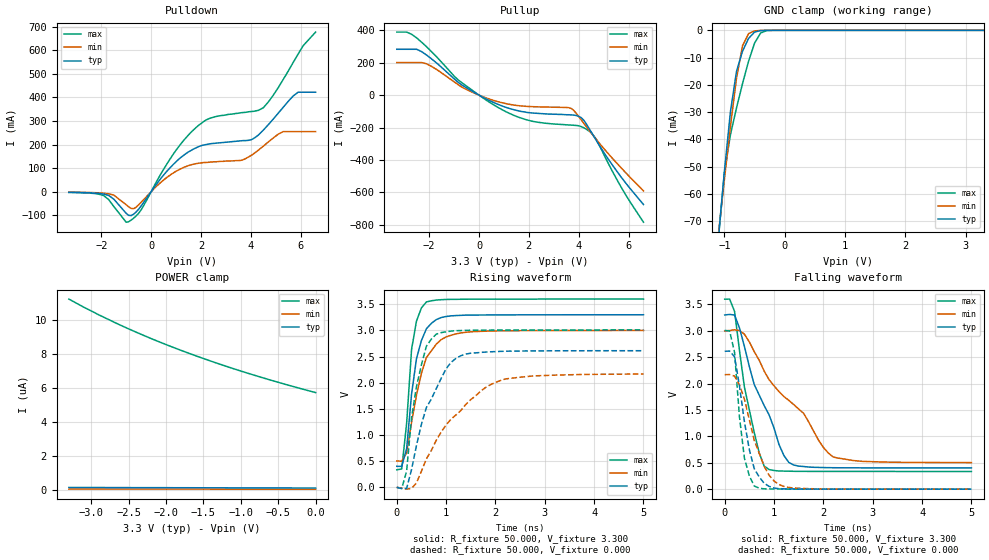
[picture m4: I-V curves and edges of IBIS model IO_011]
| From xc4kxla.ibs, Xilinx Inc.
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|   Model IO_011
[Model]   IO_011
Model_type   I/O
Polarity   Non-Inverting
Enable   Active-Low
Vinl =   0.800V
Vinh =   2.000V
Vmeas =   1.650V
Cref =  50.000pF
Rref =   1.000M
Vref =  0.000V
C_comp   7.300pF   5.500pF   8.800pF
[Temperature Range]   50.000   100.000   0.000
[Voltage Range]   3.300V   3.000V   3.600V
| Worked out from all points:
|   slope of the pulldown table from 0 to 0.495 V, typ, clamps not added: 7.07 ohm
|   slope of the pullup table from 0 to 0.495 V, typ, clamps not added: 12.6 ohm
|   GND clamp passes 1 mA (typ) near -0.52 V on its own axis
|   rising waveform, R_fixture 50.000, V_fixture 3.300: 20-80 % time 251ps typ, 356ps min, 184ps max; typ from 0.402 V to 3.3 V
|   rising waveform, R_fixture 50.000, V_fixture 0.000: 20-80 % time 564ps typ, 1.02ns min, 290ps max; typ from 0 V to 2.61 V
|   falling waveform, R_fixture 50.000, V_fixture 3.300: 20-80 % time 661ps typ, 1.19ns min, 364ps max; typ from 3.3 V to 0.403 V
|   falling waveform, R_fixture 50.000, V_fixture 0.000: 20-80 % time 287ps typ, 411ps min, 183ps max; typ from 2.61 V to 0.001 V
[Pulldown]
| voltage   I(typ)   I(min)   I(max)
-3.3V     -2.3mA     -1.8mA     -2.8mA
-1.9V     -9.7mA     -6.1mA     -16.3mA
-900mV    -100mA     -63.86mA   -127mA
-400mV    -59.92mA   -44.53mA   -76.62mA
700mV     94.99mA    66.07mA    129mA
1.6V      175mA      114mA      252mA
2.3V      202mA      125mA      309mA
3.6V      216mA      133mA      335mA
4.5V      261mA      193mA      356mA
5.3V      358mA      255mA      476mA
5.9V      422mA      255mA      584mA
6.6V      422mA      255mA      677mA
[Pullup]
| voltage   I(typ)   I(min)   I(max)
-3.3V     283mA      201mA      389mA
-2.9V     283mA      201mA      389mA
-2.3V     268mA      201mA      326mA
-800mV    74.73mA    60.76mA    89.48mA
1.1V      -76.41mA   -53.09mA   -104mA
2.1V      -110mA     -70.85mA   -160mA
3.7V      -122mA     -82.08mA   -185mA
4.1V      -139mA     -152mA     -194mA
4.5V      -227mA     -233mA     -231mA
4.7V      -278mA     -272mA     -271mA
5.5V      -463mA     -415mA     -512mA
6.6V      -675mA     -591mA     -784mA
[GND_clamp]
| voltage   I(typ)   I(min)   I(max)
-3.3V     -539mA     -461mA     -635mA
-1.1V     -76.29mA   -74.81mA   -76.3mA
-1V       -51.66mA   -54.6mA    -52.25mA
-900mV    -29.77mA   -35.09mA   -38.23mA
-800mV    -15.1mA    -17.65mA   -28.49mA
-700mV    -7.645mA   -5.66mA    -19.53mA
-600mV    -2.968mA   -1.205mA   -11.34mA
-500mV    -649uA     -202uA     -4.68mA
-400mV    -83.34uA   -28.89uA   -976uA
-300mV    -8.303uA   -3.567uA   -95.2uA
3.3V      91.94nA    24.12nA    4.611uA
[POWER_clamp]
| voltage   I(typ)   I(min)   I(max)
-3.3V     126nA      27.82nA    11.23uA
-2.9V     121nA      27.69nA    10.3uA
-2.6V     117nA      27.29nA    9.671uA
-2.2V     113nA      27nA       8.903uA
-1.8V     109nA      25.98nA    8.207uA
-1.4V     104nA      25.34nA    7.571uA
-1V       101nA      24.85nA    6.988uA
-600mV    97.4nA     24.51nA    6.451uA
0V        91.93nA    23.77nA    5.718uA
[Ramp]
| variable   typ   min   max
dV/dt_r   1.567/0.538n   1.299/1.004n   1.805/0.304n
dV/dt_f   1.738/0.635n   1.497/1.185n   1.958/0.357n
R_load = 50.000
[Rising Waveform]
R_fixture = 50.000
V_fixture = 3.300
V_fixture_min = 3.000
V_fixture_max = 3.600
L_fixture = 0.000H
C_fixture = 0.000F
| time   V(typ)   V(min)   V(max)
0s        402mV      503mV      335mV
100ps     401mV      499mV      351mV
200ps     739mV      661mV      1.226V
300ps     1.786V     1.245V     2.639V
400ps     2.461V     1.764V     3.18V
500ps     2.808V     2.183V     3.43V
600ps     3.03V      2.48V      3.543V
900ps     3.245V     2.823V     3.586V
1.4ns     3.291V     2.963V     3.595V
5ns       3.298V     2.998V     3.598V
[Rising Waveform]
R_fixture = 50.000
V_fixture = 0.000
V_fixture_min = 0.000
V_fixture_max = 0.000
L_fixture = 0.000H
C_fixture = 0.000F
| time   V(typ)   V(min)   V(max)
0s        0V         0V         0V
100ps     -22.6mV    -15.69mV   -24.1mV
200ps     -20.82mV   -35.23mV   312mV
300ps     343mV      -18.97mV   1.334V
500ps     1.206V     309mV      2.343V
600ps     1.525V     543mV      2.696V
800ps     1.886V     899mV      2.927V
1.2ns     2.465V     1.384V     2.994V
2.1ns     2.598V     2.041V     3.006V
5ns       2.611V     2.165V     3.008V
[Falling Waveform]
R_fixture = 50.000
V_fixture = 3.300
V_fixture_min = 3.000
V_fixture_max = 3.600
L_fixture = 0.000H
C_fixture = 0.000F
| time   V(typ)   V(min)   V(max)
0s        3.3V       3V         3.6V
100ps     3.311V     3.006V     3.602V
200ps     3.299V     3.02V      3.368V
400ps     2.703V     2.936V     1.932V
600ps     1.98V      2.604V     1.068V
800ps     1.584V     2.238V     438mV
900ps     1.408V     2.074V     372mV
1.3ns     506mV      1.683V     341mV
2.2ns     407mV      609mV      337mV
5ns       403mV      504mV      336mV
[Falling Waveform]
R_fixture = 50.000
V_fixture = 0.000
V_fixture_min = 0.000
V_fixture_max = 0.000
L_fixture = 0.000H
C_fixture = 0.000F
| time   V(typ)   V(min)   V(max)
0s        2.613V     2.169V     3.009V
100ps     2.617V     2.172V     2.996V
200ps     2.508V     2.143V     2.592V
300ps     1.952V     1.976V     1.361V
400ps     1.277V     1.704V     585mV
500ps     746mV      1.313V     252mV
600ps     387mV      925mV      59.41mV
900ps     53.33mV    264mV      5.553mV
1.2ns     6.806mV    52.26mV    2.62mV
5ns       740uV      819uV      655uV
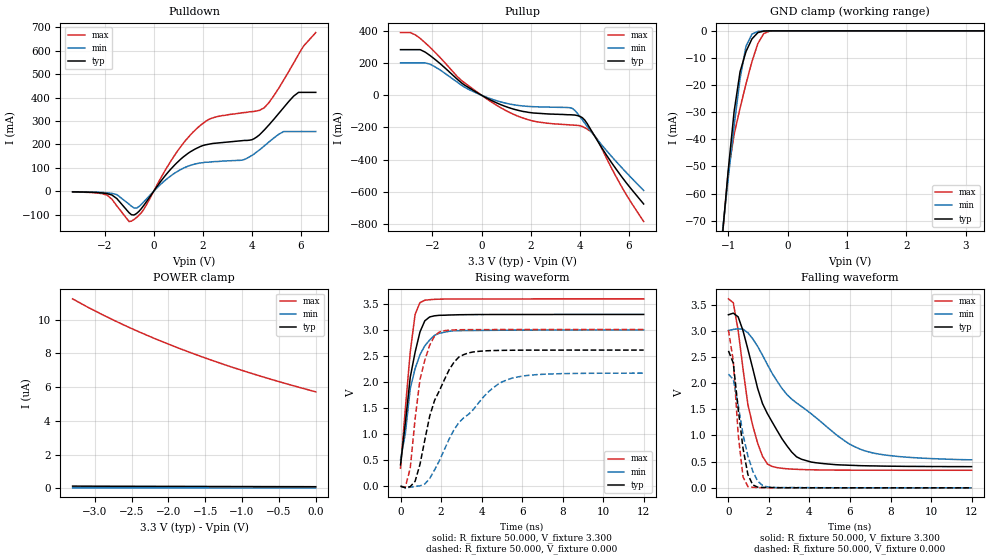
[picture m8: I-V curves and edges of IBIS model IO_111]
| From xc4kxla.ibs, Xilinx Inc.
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|   Model IO_111
[Model]   IO_111
Model_type   I/O
Polarity   Non-Inverting
Enable   Active-Low
Vinl =   0.800V
Vinh =   2.000V
Vmeas =   1.650V
Cref =  50.000pF
Rref =   1.000M
Vref =  0.000V
C_comp   7.300pF   5.500pF   8.800pF
[Temperature Range]   50.000   100.000   0.000
[Voltage Range]   3.300V   3.000V   3.600V
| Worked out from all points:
|   slope of the pulldown table from 0 to 0.495 V, typ, clamps not added: 7.07 ohm
|   slope of the pullup table from 0 to 0.495 V, typ, clamps not added: 12.6 ohm
|   GND clamp passes 1 mA (typ) near -0.52 V on its own axis
|   rising waveform, R_fixture 50.000, V_fixture 3.300: 20-80 % time 640ps typ, 702ps min, 467ps max; typ from 0.4 V to 3.3 V
|   rising waveform, R_fixture 50.000, V_fixture 0.000: 20-80 % time 1.21ns typ, 2.3ns min, 646ps max; typ from -0.011 V to 2.61 V
|   falling waveform, R_fixture 50.000, V_fixture 3.300: 20-80 % time 1.66ns typ, 3.56ns min, 846ps max; typ from 3.31 V to 0.405 V
|   falling waveform, R_fixture 50.000, V_fixture 0.000: 20-80 % time 511ps typ, 699ps min, 361ps max; typ from 2.62 V to 0 V
[Pulldown]
| voltage   I(typ)   I(min)   I(max)
-3.3V     -2.3mA     -1.8mA     -2.8mA
-1.9V     -9.7mA     -6.1mA     -16.3mA
-900mV    -100mA     -63.86mA   -127mA
-400mV    -59.92mA   -44.53mA   -76.62mA
700mV     94.99mA    66.07mA    129mA
1.6V      175mA      114mA      252mA
2.3V      202mA      125mA      309mA
3.6V      216mA      133mA      335mA
4.5V      261mA      193mA      356mA
5.3V      358mA      255mA      476mA
5.9V      422mA      255mA      584mA
6.6V      422mA      255mA      677mA
[Pullup]
| voltage   I(typ)   I(min)   I(max)
-3.3V     283mA      201mA      389mA
-2.9V     283mA      201mA      389mA
-2.3V     268mA      201mA      326mA
-800mV    74.73mA    60.76mA    89.48mA
1.1V      -76.41mA   -53.09mA   -104mA
2.1V      -110mA     -70.85mA   -160mA
3.7V      -122mA     -82.08mA   -185mA
4.1V      -139mA     -152mA     -194mA
4.5V      -227mA     -233mA     -231mA
4.7V      -278mA     -272mA     -271mA
5.5V      -463mA     -415mA     -512mA
6.6V      -675mA     -591mA     -784mA
[GND_clamp]
| voltage   I(typ)   I(min)   I(max)
-3.3V     -539mA     -461mA     -635mA
-1.1V     -76.29mA   -74.81mA   -76.3mA
-1V       -51.66mA   -54.6mA    -52.25mA
-900mV    -29.77mA   -35.09mA   -38.23mA
-800mV    -15.1mA    -17.65mA   -28.49mA
-700mV    -7.645mA   -5.66mA    -19.53mA
-600mV    -2.968mA   -1.205mA   -11.34mA
-500mV    -649uA     -202uA     -4.68mA
-400mV    -83.34uA   -28.89uA   -976uA
-300mV    -8.303uA   -3.567uA   -95.2uA
3.3V      91.97nA    24.12nA    4.611uA
[POWER_clamp]
| voltage   I(typ)   I(min)   I(max)
-3.3V     126nA      27.82nA    11.23uA
-2.9V     121nA      27.69nA    10.3uA
-2.6V     117nA      27.28nA    9.671uA
-2.2V     113nA      27nA       8.903uA
-1.8V     109nA      25.98nA    8.207uA
-1.4V     104nA      25.34nA    7.571uA
-1V       101nA      24.85nA    6.988uA
-600mV    97.4nA     24.51nA    6.451uA
0V        91.96nA    23.79nA    5.718uA
[Ramp]
| variable   typ   min   max
dV/dt_r   1.567/1.194n   1.301/2.290n   1.805/0.631n
dV/dt_f   1.737/1.662n   1.479/3.562n   1.958/0.840n
R_load = 50.000
[Rising Waveform]
R_fixture = 50.000
V_fixture = 3.300
V_fixture_min = 3.000
V_fixture_max = 3.600
L_fixture = 0.000H
C_fixture = 0.000F
| time   V(typ)   V(min)   V(max)
0s        400mV      500mV      337mV
240ps     1.216V     1.008V     1.495V
480ps     2.089V     1.87V      2.576V
720ps     2.571V     2.255V     3.301V
960ps     2.962V     2.524V     3.527V
1.2ns     3.177V     2.696V     3.573V
1.44ns    3.251V     2.807V     3.583V
1.68ns    3.273V     2.898V     3.59V
2.4ns     3.288V     2.974V     3.596V
12ns      3.299V     2.999V     3.599V
[Rising Waveform]
R_fixture = 50.000
V_fixture = 0.000
V_fixture_min = 0.000
V_fixture_max = 0.000
L_fixture = 0.000H
C_fixture = 0.000F
| time   V(typ)   V(min)   V(max)
0s        -11.35mV   -7.345mV   -14.91mV
240ps     -41.65mV   -42.72mV   -25.58mV
480ps     -18.94mV   -30.98mV   337mV
720ps     83.46mV    -15.01mV   1.29V
960ps     410mV      -4.839mV   2.047V
1.2ns     883mV      33.28mV    2.42V
1.92ns    1.832V     481mV      2.96V
2.88ns    2.478V     1.214V     3.004V
5.04ns    2.607V     2.005V     3.008V
12ns      2.612V     2.168V     3.009V
[Falling Waveform]
R_fixture = 50.000
V_fixture = 3.300
V_fixture_min = 3.000
V_fixture_max = 3.600
L_fixture = 0.000H
C_fixture = 0.000F
| time   V(typ)   V(min)   V(max)
0s        3.305V     3.003V     3.608V
240ps     3.335V     3.025V     3.533V
480ps     3.264V     3.037V     3.003V
960ps     2.644V     2.961V     1.59V
1.2ns     2.278V     2.845V     1.187V
1.68ns    1.61V      2.533V     604mV
1.92ns    1.419V     2.355V     456mV
3.36ns    593mV      1.622V     354mV
6.24ns    428mV      784mV      338mV
12ns      405mV      535mV      336mV
[Falling Waveform]
R_fixture = 50.000
V_fixture = 0.000
V_fixture_min = 0.000
V_fixture_max = 0.000
L_fixture = 0.000H
C_fixture = 0.000F
| time   V(typ)   V(min)   V(max)
0s        2.616V     2.171V     3.014V
240ps     2.383V     2.068V     2.425V
480ps     1.51V      1.587V     1.022V
720ps     754mV      1.015V     209mV
960ps     254mV      609mV      23.71mV
1.2ns     56.77mV    318mV      9.442mV
1.44ns    13.76mV    130mV      5.143mV
1.68ns    7.242mV    47.2mV     3.084mV
1.92ns    7.795mV    18.95mV    2.522mV
12ns      351uV      548uV      228uV
